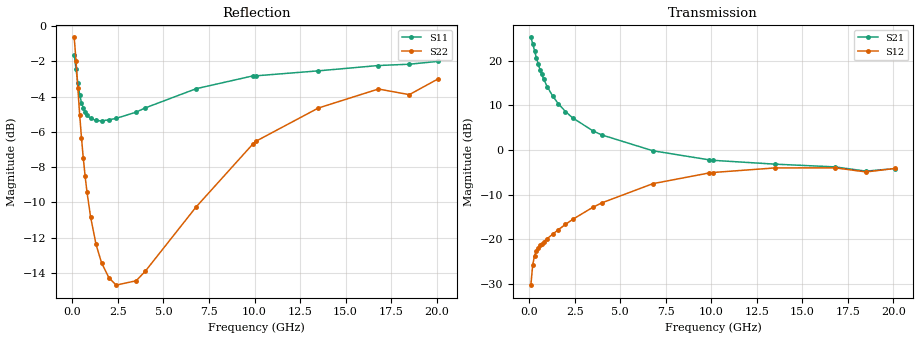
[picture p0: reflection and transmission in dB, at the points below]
!  Infineon Technologies AG
! BFR380L3 , PF131585-7, No.6, Th 09.10.01, soldered on pcb-board, measured with PP GSG850
!  Vce=1.75 V,  Ic=6.0 mA
! Common Emitter S-Parameters:  15. November 2001
#  GHz  S  MA  R  50
! f  S11  S21  S12  S22
! GHz  Mag  Ang  Mag  Ang  Mag  Ang  Mag  Ang
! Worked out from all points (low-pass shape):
!   201 points, 100 MHz to 20.1 GHz, reference 50 ohm
!   highest |S21| = 25.25 dB at 100 MHz (marker M1); lowest = -4.7 dB at 18.5 GHz (marker M2)
!   |S21| within 3 dB of the highest: start of sweep to 301.3 MHz
!   lowest |S11| = -5.4 dB at 1.6 GHz (marker M3), VSWR 3.33, Z = 15 - j1.28 ohm
!   |S11| at or under -10 dB: nowhere
!   |S22| runs from -14.8 to -0.6 dB; largest |S21 - S12| = 18
!   S11 on the Smith chart (normalised r, x): 100 MHz: 1.02, -2.97; 400 MHz: 0.35, -0.74; 1 GHz: 0.31, -0.21; 4 GHz: 0.30, +0.36; 9.9 GHz: 0.38, +1.14; 20.1 GHz: 0.96, +2.56
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0.1  0.8279 -33.8  18.3 158.0  0.03076 71.3  0.9294 -21.4
0.2  0.7547 -62.9  15.59 140.3  0.05169 60.1  0.7966 -38.6
0.3  0.6894 -85.5  12.99 127.4  0.06566 51.9  0.6662 -50.8
0.4  0.639 -102.8  10.88 117.9  0.07405 47.1  0.5611 -59.6
0.5  0.6061 -116.1  9.248 110.7  0.08048 44.6  0.4819 -66.1
0.6  0.5858 -126.9  7.993 105.2  0.08552 43.3  0.4217 -71.2
0.7  0.5689 -135.5  7.028 100.5  0.08972 42.9  0.3751 -75.4
0.8  0.5595 -142.8  6.253 96.6  0.09404 43.0  0.3389 -78.9
1  0.547 -154.4  5.122 90.1  0.1021 43.8  0.2875 -84.6
1.3  0.5399 -167.1  4.024 82.3  0.1145 45.7  0.2401 -91.9
1.6  0.5384 -176.8  3.321 75.7  0.128 47.5  0.2131 -98.3
2  0.5423 172.9  2.702 68.1  0.1472 49.3  0.1934 -106.1
2.4  0.5474 164.1  2.293 61.3  0.1678 50.3  0.1841 -113.9
3.5  0.5701 144.8  1.646 45.1  0.2287 49.9  0.1894 -133.9
4  0.5862 137.6  1.478 38.8  0.2567 48.7  0.2015 -144.0
6.8  0.6647 104.0  0.9828 10.9  0.421 34.1  0.3071 170.6
9.9  0.7224 79.0  0.7776 -7.4  0.5553 13.6  0.4624 133.6
10.1  0.7231 77.6  0.7685 -8.3  0.5614 12.3  0.4721 131.5
13.5  0.7468 59.7  0.6964 -22.6  0.6318 -9.4  0.5856 100.3
16.8  0.7733 47.6  0.6488 -33.4  0.6334 -25.7  0.6632 77.7
18.5  0.7799 45.7  0.5814 -40.7  0.5696 -34.3  0.6393 71.9
20.1  0.7948 38.4  0.6216 -44.2  0.6234 -39.4  0.7094 61.0
